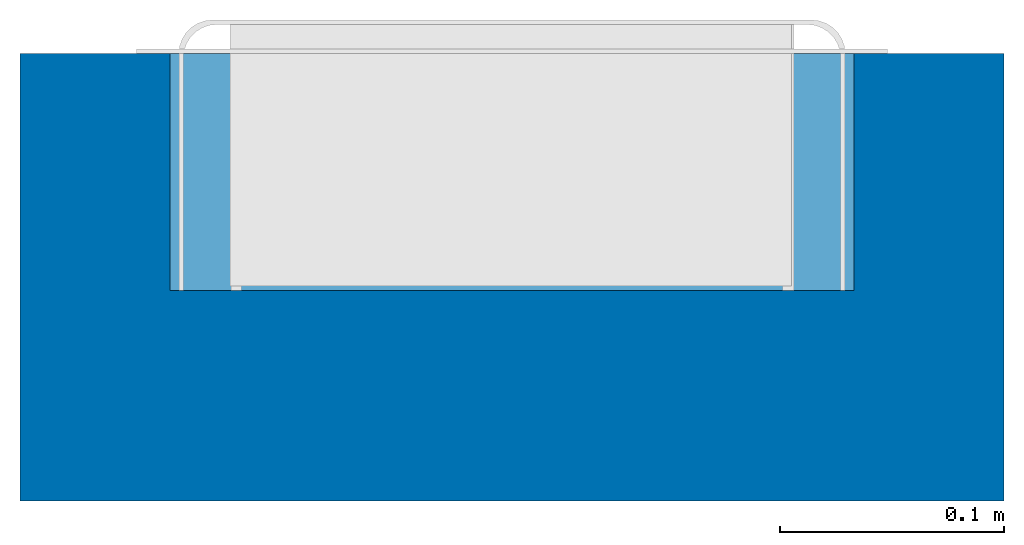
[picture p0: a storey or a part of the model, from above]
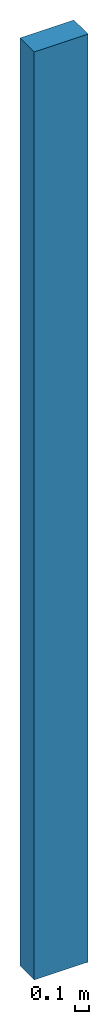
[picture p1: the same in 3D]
Properties of the parts of a building model (IFC2X3)

# File
Description: ViewDefinition [CoordinationView]
File name: Project Number
Time: 2017-11-08T09:32:35
Written by: The EXPRESS Data Manager Version 5.02.0100.07 : 28 Aug 2013
Made in: 20140606_1530(x64) - Exporter 2015.0.2014.0606 - Default UI
Comment: STEP Physical File produced by: The EXPRESS Data Manager Version 5.02.0100.07 : 28 Aug 2013 * Module: EDMstepFileFactory/EDMstandAlone * Creation date: Wed Nov 08 09:32:35 2017 * Host: DESKTOP-FI6EGIK * Database: C:\Users\CERTIF~1\AppData\Local\Temp\{1653991D-2356-4F6A-9CD4-63EE6F678F24}\ifc * Database version: 5507 * Database creation date: Wed Nov 08 09:32:34 2017 * Schema: IFC2X3 * Model: DataRepository.ifc * Model creation date: Wed Nov 08 09:32:34 2017 * Header model: DataRepository.ifc_HeaderModel * Header model creation date: Wed Nov 08 09:32:34 2017 * EDMuser: sdai-user * EDMgroup: sdai-group * License ID and type: 5605 : Permanent license. Expiry date: * EDMstepFileFactory options: 020000

# IfcProject, Project Number
LongName: Project Name; Phase: Project Status

# IfcSite, Default
RefLatitude: 42, 21, 30, 344238; RefLongitude: -71, -3, -35, -194702; RefElevation: 0 mm
Other - Category: Project Information; Client Name: Owner; Project Address: ## Street City, State Zip; Project Issue Date: Issue Date; Project Name: Project Name; Project Number: Project Number; Project Status: Project Status

# IfcBuilding
Pset_BuildingCommon - NumberOfStoreys: 1
Other - Category: Project Information; Client Name: Owner; Project Address: ## Street City, State Zip; Project Issue Date: Issue Date; Project Name: Project Name; Project Number: Project Number; Project Status: Project Status

# IfcBuildingStorey, Level 1
LongName: Level 1; Elevation: 0 mm
Other - Category: Levels; Family Name: Level; Family: Level: 8mm Head; Family and Type: Level: 8mm Head; Type: Level: 8mm Head; Type Id: Level: 8mm Head
Identity Data - Type Name: 8mm Head; Structural: no; Building Story: yes; Name: Level 1
Graphics - Color: 0; Line Pattern: Center; Line Weight: 1; Symbol: M_Level Head - Circle: M_Level Head - Circle; Symbol at End 1 Default: no; Symbol at End 2 Default: yes
Constraints - Elevation Base: Project Base Point; Elevation: 0 mm
Dimensions - Computation Height: 0 mm

# IfcFurnishingElement: d_line_Washroom_RecessedSanitaryPanels_PaperTowelDispenser_With_SquareOpeningWasteBin_PanelSize7, 14710007010b:d_line_Washroom_RecessedSanitaryPanels_PaperTowelDispenser_With_SquareOpeningWasteBin_PanelSize7:194301
In: Level 1
Type - ElementType: d_line_Washroom_RecessedSanitaryPanels_PaperTowelDispenser_With_SquareOpeningWasteBin_PanelSize7
Type - Data - Form: Recessed sanitary panel; IntegralAccessories: n/a; Operation: Manual; PaperTowelCapacity: 350; PaperTowelSize: 230 x 80 mm; StructuralOpeningSizeRecommendation: 106 x 306 x 1092 mm; WasteBinCapacity: 12 L; WasteBinForm: Recessed waste bin with a square opening; WasteBinProtruded: no; WasteBinRecessed: yes; WasteBinSize: 12 L
Type - Dimensions - BendRadius: 15 mm; Cut1: 29.5 mm; Cut2: 445 mm; Cut3: 145 mm; GapThickness: 4 mm; PanelProtrusion: 15 mm; PanelSize: 7; SheetThickness: 2 mm; SkirtWidth: 15 mm; SquareOpeningWidth: 242 mm; StructuralOpeningDepth: 106 mm; StructuralOpeningHeight: 1092 mm; StructuralOpeningWidth: 306 mm
Type - General - Author: Gytautas Balevičius; BIMObjectName: d_line_Washroom_RecessedSanitaryPanels_PaperTowelDispenser_With_SquareOpeningWasteBin_PanelSize7; DesignCountry: Denmark; ManufacturerName: d line; ManufacturerURL: www.dline.com; MasterFormat2014Code: 10 28 13; MasterFormat2014Description: Toilet Accessories; NBSCertification: n/a; NBSDescription: Paper towel dispensers; NBSNote: 45-35-72/344:Paper towel dispensers; 45-35-72/380:Waste bins;; NBSOfficeMasterTag: n/a; NBSReference: 45-35-72/344; NBSTypeID: n/a; OmniclassCode: 23-31 25 19 11; OmniclassDescription: Toilet, Bath, and Laundry Accessories; ProductFamily: Sanitary panels; ProductGroup: Recessed panels; ProductInformation: http://dline.com/product/knud-holscher-collection-sanitary-panel-hl/?attribute_pa_material=satin-stainless-steel-aisi-316&attribute_pa_item=hl-module-size-7#; ProductionCountry: Lithuania; ProductSKU: 14710007010; Revision: n/a; Uniclass2015Code: Pr_40_70_22_62; Uniclass2015Title: Paper towel dispensers; Uniclass2015Version: Products v1.5; UNSPSCCode: Search Code Search Title sANITARY Search Code Title 40151519 Sanitary pumps 47131703 Sanitary waste receptacles 47131702 Sanitary goods dispensers 76121602 Sanitary landfill operations 30181500; Version: 1; Weight Net (Kg): 12
Type - Identity Data - Description: Recessed sanitary panel with paper towel dispenser and a waste bin; Manufacturer: info@dline.com; Type Image: Raster image: Image.jpg; Type Name: d_line_Washroom_RecessedSanitaryPanels_PaperTowelDispenser_With_SquareOpeningWasteBin_PanelSize7; URL: www.dline.com
Type - Materials and Finishes - MainMaterial: AISI 316
Type - Other - AccessibilityPerformance: n/a; AssetType: Fixed; Category: Pr_40_70_22_62:Paper towel dispenser; CodePerformance: n/a; Color: Silver; Constituents: Paper towel dispenser; Waste bin;; DurationUnit: year; ExpectedLife: 20 years; Family Name: 14710007010b; Features: n/a; Finish: Polished/Satin; Grade: n/a; Material: Stainless steel AISI 316; ModelNumber: n/a; ModelReference: 45-35-72/344; Name: d_line_Washroom_RecessedSanitaryPanels_PaperTowelDispenser_With_SquareOpeningWasteBin_PanelSize7; ReplacementCost: n/a; Shape: n/a; Size: 121 x 336 x 1122 mm; SustainabilityPerformance: n/a; TagNumber: n/a; WarrantyDescription: 20 years (non-mechanical/-electronic parts) excluding labor; WarrantyDurationLabor: n/a; WarrantyDurationParts: 20; WarrantyDurationUnit: year; WarrantyGuarantorLabor: n/a; WarrantyGuarantorParts: claim@dline.com
Pset_ManufacturerTypeInformation - ModelReference: 45-35-72/344; Manufacturer: info@dline.com
Constraints - Level: Level: Level 1; Elevation: 985 mm
Dimensions - Area: 0.738684 m2; PlacementHeight: 1000 mm; Volume: 0.00161333 m3
Other - Category: Furniture; Family: 14710007010b: d_line_Washroom_RecessedSanitaryPanels_PaperTowelDispenser_With_SquareOpeningWasteBin_PanelSize7; Family and Type: 14710007010b: d_line_Washroom_RecessedSanitaryPanels_PaperTowelDispenser_With_SquareOpeningWasteBin_PanelSize7; Host Id: Basic Wall: Generic - 200mm; Type: 14710007010b: d_line_Washroom_RecessedSanitaryPanels_PaperTowelDispenser_With_SquareOpeningWasteBin_PanelSize7; Type Id: 14710007010b: d_line_Washroom_RecessedSanitaryPanels_PaperTowelDispenser_With_SquareOpeningWasteBin_PanelSize7; AssetIdentifier: n/a; BarCode: n/a; InstallationDate: 1900-12-31T23:59:59; SerialNumber: n/a; WarrantyStartDate: 1900-12-31T23:59:59
Phasing - Phase Created: New Construction

# IfcOpeningElement: Opening (4)
In: Level 1
Pset_ManufacturerTypeInformation - ModelReference: 45-35-72/344; Manufacturer: info@dline.com
Name (14710007010b:d_line_Washroom_RecessedSanitaryPanels_PaperTowelDispenser_With_SquareOpeningWasteBin_PanelSize7:194301:...)
1
2
3
4

# IfcOpeningElement: Recess, Basic Wall:Generic - 200mm:193172
In: Level 1
Constraints - Elevation: 985 mm; Level: Level: Level 1
Dimensions - Area: 0.738684 m2; PlacementHeight: 1000 mm; Volume: 0.00161333 m3
Other - AssetIdentifier: n/a; BarCode: n/a; Category: Furniture; Family: 14710007010b: d_line_Washroom_RecessedSanitaryPanels_PaperTowelDispenser_With_SquareOpeningWasteBin_PanelSize7; Family and Type: 14710007010b: d_line_Washroom_RecessedSanitaryPanels_PaperTowelDispenser_With_SquareOpeningWasteBin_PanelSize7; Host Id: Basic Wall: Generic - 200mm; InstallationDate: 1900-12-31T23:59:59; SerialNumber: n/a; Type: 14710007010b: d_line_Washroom_RecessedSanitaryPanels_PaperTowelDispenser_With_SquareOpeningWasteBin_PanelSize7; Type Id: 14710007010b: d_line_Washroom_RecessedSanitaryPanels_PaperTowelDispenser_With_SquareOpeningWasteBin_PanelSize7; WarrantyStartDate: 1900-12-31T23:59:59
Phasing - Phase Created: New Construction

# IfcWallStandardCase: Basic Wall:Generic - 200mm, Basic Wall:Generic - 200mm:193172
In: Level 1
Type - PredefinedType: STANDARD; Material: Default Wall 200 mm
Type - Analytical Properties - Absorptance: 0.1; Roughness: 1
Type - Construction - Function: Exterior; Width: 200 mm; Wrapping at Inserts: Do not wrap
Type - Graphics - Coarse Scale Fill Color: 0
Type - Identity Data - Type Name: Generic - 200mm
Type - Other - Category: Walls; Family Name: Basic Wall
Constraints - Base Constraint: Level: Level 1; Base Extension Distance: 0 mm; Base is Attached: no; Base Offset: 0 mm; Location Line: Wall Centerline; Related to Mass: no; Room Bounding: yes; Top Extension Distance: 0 mm; Top is Attached: no; Top Offset: 0 mm; Unconnected Height: 8000 mm
Dimensions - Area: 3.52 m2; Length: 440 mm; Volume: 0.66858 m3
Other - Family: Basic Wall: Generic - 200mm; Family and Type: Basic Wall: Generic - 200mm; Type: Basic Wall: Generic - 200mm; Type Id: Basic Wall: Generic - 200mm
Phasing - Phase Created: New Construction
Structural - Enable Analytical Model: no; Structural: no; Structural Usage: Non-bearing
Pset_WallCommon - Reference: Generic - 200mm; LoadBearing: no; ExtendToStructure: no; IsExternal: yes
